VERSION 5.8 ;

BUSBITCHARS "[]" ;

DIVIDERCHAR "/" ;

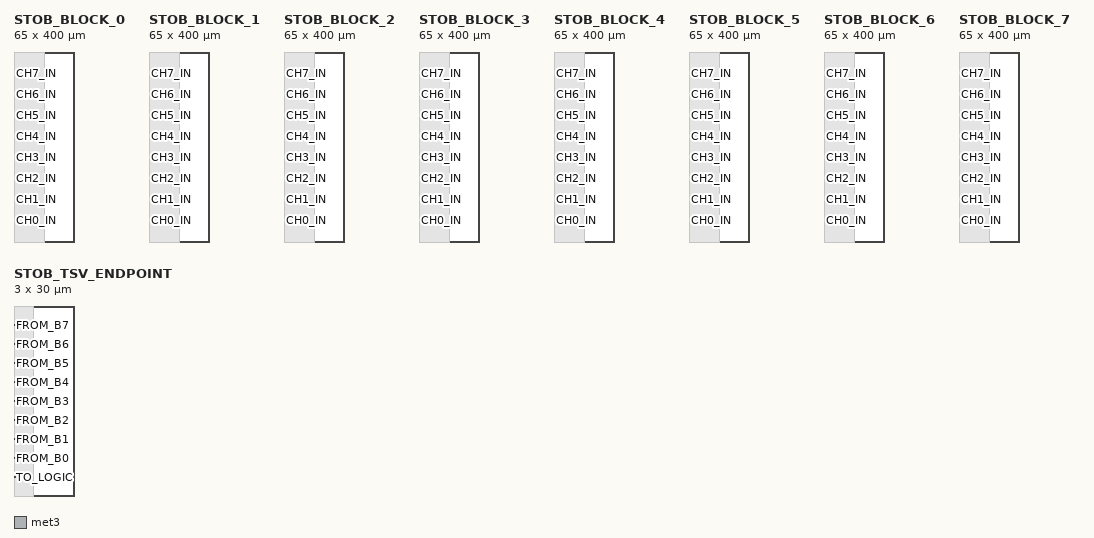
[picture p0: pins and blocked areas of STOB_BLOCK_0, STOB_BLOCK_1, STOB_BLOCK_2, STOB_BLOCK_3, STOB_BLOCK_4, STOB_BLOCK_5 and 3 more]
MACRO STOB_BLOCK_0
  CLASS BLOCK ;
  ORIGIN 0 0 ;
  FOREIGN STOB_BLOCK_0 0 0 ;
  SIZE 65.000000 BY 400.000000 ;
  SYMMETRY X Y ;
  PIN CH0_IN
    DIRECTION INPUT ;
    USE SIGNAL ;
    PORT
      LAYER met3 ;
        RECT 0.000000 44.244444 0.200000 44.644444 ;
    END
  END CH0_IN
  PIN CH0_OUT
    DIRECTION OUTPUT ;
    USE SIGNAL ;
    PORT
      LAYER met3 ;
        RECT 64.800000 44.244444 65.000000 44.644444 ;
    END
  END CH0_OUT
  PIN CH1_IN
    DIRECTION INPUT ;
    USE SIGNAL ;
    PORT
      LAYER met3 ;
        RECT 0.000000 88.688889 0.200000 89.088889 ;
    END
  END CH1_IN
  PIN CH1_OUT
    DIRECTION OUTPUT ;
    USE SIGNAL ;
    PORT
      LAYER met3 ;
        RECT 64.800000 88.688889 65.000000 89.088889 ;
    END
  END CH1_OUT
  PIN CH2_IN
    DIRECTION INPUT ;
    USE SIGNAL ;
    PORT
      LAYER met3 ;
        RECT 0.000000 133.133333 0.200000 133.533333 ;
    END
  END CH2_IN
  PIN CH2_OUT
    DIRECTION OUTPUT ;
    USE SIGNAL ;
    PORT
      LAYER met3 ;
        RECT 64.800000 133.133333 65.000000 133.533333 ;
    END
  END CH2_OUT
  PIN CH3_IN
    DIRECTION INPUT ;
    USE SIGNAL ;
    PORT
      LAYER met3 ;
        RECT 0.000000 177.577778 0.200000 177.977778 ;
    END
  END CH3_IN
  PIN CH3_OUT
    DIRECTION OUTPUT ;
    USE SIGNAL ;
    PORT
      LAYER met3 ;
        RECT 64.800000 177.577778 65.000000 177.977778 ;
    END
  END CH3_OUT
  PIN CH4_IN
    DIRECTION INPUT ;
    USE SIGNAL ;
    PORT
      LAYER met3 ;
        RECT 0.000000 222.022222 0.200000 222.422222 ;
    END
  END CH4_IN
  PIN CH4_OUT
    DIRECTION OUTPUT ;
    USE SIGNAL ;
    PORT
      LAYER met3 ;
        RECT 64.800000 222.022222 65.000000 222.422222 ;
    END
  END CH4_OUT
  PIN CH5_IN
    DIRECTION INPUT ;
    USE SIGNAL ;
    PORT
      LAYER met3 ;
        RECT 0.000000 266.466667 0.200000 266.866667 ;
    END
  END CH5_IN
  PIN CH5_OUT
    DIRECTION OUTPUT ;
    USE SIGNAL ;
    PORT
      LAYER met3 ;
        RECT 64.800000 266.466667 65.000000 266.866667 ;
    END
  END CH5_OUT
  PIN CH6_IN
    DIRECTION INPUT ;
    USE SIGNAL ;
    PORT
      LAYER met3 ;
        RECT 0.000000 310.911111 0.200000 311.311111 ;
    END
  END CH6_IN
  PIN CH6_OUT
    DIRECTION OUTPUT ;
    USE SIGNAL ;
    PORT
      LAYER met3 ;
        RECT 64.800000 310.911111 65.000000 311.311111 ;
    END
  END CH6_OUT
  PIN CH7_IN
    DIRECTION INPUT ;
    USE SIGNAL ;
    PORT
      LAYER met3 ;
        RECT 0.000000 355.355556 0.200000 355.755556 ;
    END
  END CH7_IN
  PIN CH7_OUT
    DIRECTION OUTPUT ;
    USE SIGNAL ;
    PORT
      LAYER met3 ;
        RECT 64.800000 355.355556 65.000000 355.755556 ;
    END
  END CH7_OUT
  OBS
    LAYER met1 ;
      RECT 0 0 65.000000 400.000000 ;
    LAYER met2 ;
      RECT 0 0 65.000000 400.000000 ;
    LAYER met4 ;
      RECT 0 0 65.000000 400.000000 ;
  END
END STOB_BLOCK_0

MACRO STOB_BLOCK_1
  CLASS BLOCK ;
  ORIGIN 0 0 ;
  FOREIGN STOB_BLOCK_1 0 0 ;
  SIZE 65.000000 BY 400.000000 ;
  SYMMETRY X Y ;
  PIN CH0_IN
    DIRECTION INPUT ;
    USE SIGNAL ;
    PORT
      LAYER met3 ;
        RECT 0.000000 44.244444 0.200000 44.644444 ;
    END
  END CH0_IN
  PIN CH0_OUT
    DIRECTION OUTPUT ;
    USE SIGNAL ;
    PORT
      LAYER met3 ;
        RECT 64.800000 44.244444 65.000000 44.644444 ;
    END
  END CH0_OUT
  PIN CH1_IN
    DIRECTION INPUT ;
    USE SIGNAL ;
    PORT
      LAYER met3 ;
        RECT 0.000000 88.688889 0.200000 89.088889 ;
    END
  END CH1_IN
  PIN CH1_OUT
    DIRECTION OUTPUT ;
    USE SIGNAL ;
    PORT
      LAYER met3 ;
        RECT 64.800000 88.688889 65.000000 89.088889 ;
    END
  END CH1_OUT
  PIN CH2_IN
    DIRECTION INPUT ;
    USE SIGNAL ;
    PORT
      LAYER met3 ;
        RECT 0.000000 133.133333 0.200000 133.533333 ;
    END
  END CH2_IN
  PIN CH2_OUT
    DIRECTION OUTPUT ;
    USE SIGNAL ;
    PORT
      LAYER met3 ;
        RECT 64.800000 133.133333 65.000000 133.533333 ;
    END
  END CH2_OUT
  PIN CH3_IN
    DIRECTION INPUT ;
    USE SIGNAL ;
    PORT
      LAYER met3 ;
        RECT 0.000000 177.577778 0.200000 177.977778 ;
    END
  END CH3_IN
  PIN CH3_OUT
    DIRECTION OUTPUT ;
    USE SIGNAL ;
    PORT
      LAYER met3 ;
        RECT 64.800000 177.577778 65.000000 177.977778 ;
    END
  END CH3_OUT
  PIN CH4_IN
    DIRECTION INPUT ;
    USE SIGNAL ;
    PORT
      LAYER met3 ;
        RECT 0.000000 222.022222 0.200000 222.422222 ;
    END
  END CH4_IN
  PIN CH4_OUT
    DIRECTION OUTPUT ;
    USE SIGNAL ;
    PORT
      LAYER met3 ;
        RECT 64.800000 222.022222 65.000000 222.422222 ;
    END
  END CH4_OUT
  PIN CH5_IN
    DIRECTION INPUT ;
    USE SIGNAL ;
    PORT
      LAYER met3 ;
        RECT 0.000000 266.466667 0.200000 266.866667 ;
    END
  END CH5_IN
  PIN CH5_OUT
    DIRECTION OUTPUT ;
    USE SIGNAL ;
    PORT
      LAYER met3 ;
        RECT 64.800000 266.466667 65.000000 266.866667 ;
    END
  END CH5_OUT
  PIN CH6_IN
    DIRECTION INPUT ;
    USE SIGNAL ;
    PORT
      LAYER met3 ;
        RECT 0.000000 310.911111 0.200000 311.311111 ;
    END
  END CH6_IN
  PIN CH6_OUT
    DIRECTION OUTPUT ;
    USE SIGNAL ;
    PORT
      LAYER met3 ;
        RECT 64.800000 310.911111 65.000000 311.311111 ;
    END
  END CH6_OUT
  PIN CH7_IN
    DIRECTION INPUT ;
    USE SIGNAL ;
    PORT
      LAYER met3 ;
        RECT 0.000000 355.355556 0.200000 355.755556 ;
    END
  END CH7_IN
  PIN CH7_OUT
    DIRECTION OUTPUT ;
    USE SIGNAL ;
    PORT
      LAYER met3 ;
        RECT 64.800000 355.355556 65.000000 355.755556 ;
    END
  END CH7_OUT
  OBS
    LAYER met1 ;
      RECT 0 0 65.000000 400.000000 ;
    LAYER met2 ;
      RECT 0 0 65.000000 400.000000 ;
    LAYER met4 ;
      RECT 0 0 65.000000 400.000000 ;
  END
END STOB_BLOCK_1

MACRO STOB_BLOCK_2
  CLASS BLOCK ;
  ORIGIN 0 0 ;
  FOREIGN STOB_BLOCK_2 0 0 ;
  SIZE 65.000000 BY 400.000000 ;
  SYMMETRY X Y ;
  PIN CH0_IN
    DIRECTION INPUT ;
    USE SIGNAL ;
    PORT
      LAYER met3 ;
        RECT 0.000000 44.244444 0.200000 44.644444 ;
    END
  END CH0_IN
  PIN CH0_OUT
    DIRECTION OUTPUT ;
    USE SIGNAL ;
    PORT
      LAYER met3 ;
        RECT 64.800000 44.244444 65.000000 44.644444 ;
    END
  END CH0_OUT
  PIN CH1_IN
    DIRECTION INPUT ;
    USE SIGNAL ;
    PORT
      LAYER met3 ;
        RECT 0.000000 88.688889 0.200000 89.088889 ;
    END
  END CH1_IN
  PIN CH1_OUT
    DIRECTION OUTPUT ;
    USE SIGNAL ;
    PORT
      LAYER met3 ;
        RECT 64.800000 88.688889 65.000000 89.088889 ;
    END
  END CH1_OUT
  PIN CH2_IN
    DIRECTION INPUT ;
    USE SIGNAL ;
    PORT
      LAYER met3 ;
        RECT 0.000000 133.133333 0.200000 133.533333 ;
    END
  END CH2_IN
  PIN CH2_OUT
    DIRECTION OUTPUT ;
    USE SIGNAL ;
    PORT
      LAYER met3 ;
        RECT 64.800000 133.133333 65.000000 133.533333 ;
    END
  END CH2_OUT
  PIN CH3_IN
    DIRECTION INPUT ;
    USE SIGNAL ;
    PORT
      LAYER met3 ;
        RECT 0.000000 177.577778 0.200000 177.977778 ;
    END
  END CH3_IN
  PIN CH3_OUT
    DIRECTION OUTPUT ;
    USE SIGNAL ;
    PORT
      LAYER met3 ;
        RECT 64.800000 177.577778 65.000000 177.977778 ;
    END
  END CH3_OUT
  PIN CH4_IN
    DIRECTION INPUT ;
    USE SIGNAL ;
    PORT
      LAYER met3 ;
        RECT 0.000000 222.022222 0.200000 222.422222 ;
    END
  END CH4_IN
  PIN CH4_OUT
    DIRECTION OUTPUT ;
    USE SIGNAL ;
    PORT
      LAYER met3 ;
        RECT 64.800000 222.022222 65.000000 222.422222 ;
    END
  END CH4_OUT
  PIN CH5_IN
    DIRECTION INPUT ;
    USE SIGNAL ;
    PORT
      LAYER met3 ;
        RECT 0.000000 266.466667 0.200000 266.866667 ;
    END
  END CH5_IN
  PIN CH5_OUT
    DIRECTION OUTPUT ;
    USE SIGNAL ;
    PORT
      LAYER met3 ;
        RECT 64.800000 266.466667 65.000000 266.866667 ;
    END
  END CH5_OUT
  PIN CH6_IN
    DIRECTION INPUT ;
    USE SIGNAL ;
    PORT
      LAYER met3 ;
        RECT 0.000000 310.911111 0.200000 311.311111 ;
    END
  END CH6_IN
  PIN CH6_OUT
    DIRECTION OUTPUT ;
    USE SIGNAL ;
    PORT
      LAYER met3 ;
        RECT 64.800000 310.911111 65.000000 311.311111 ;
    END
  END CH6_OUT
  PIN CH7_IN
    DIRECTION INPUT ;
    USE SIGNAL ;
    PORT
      LAYER met3 ;
        RECT 0.000000 355.355556 0.200000 355.755556 ;
    END
  END CH7_IN
  PIN CH7_OUT
    DIRECTION OUTPUT ;
    USE SIGNAL ;
    PORT
      LAYER met3 ;
        RECT 64.800000 355.355556 65.000000 355.755556 ;
    END
  END CH7_OUT
  OBS
    LAYER met1 ;
      RECT 0 0 65.000000 400.000000 ;
    LAYER met2 ;
      RECT 0 0 65.000000 400.000000 ;
    LAYER met4 ;
      RECT 0 0 65.000000 400.000000 ;
  END
END STOB_BLOCK_2

MACRO STOB_BLOCK_3
  CLASS BLOCK ;
  ORIGIN 0 0 ;
  FOREIGN STOB_BLOCK_3 0 0 ;
  SIZE 65.000000 BY 400.000000 ;
  SYMMETRY X Y ;
  PIN CH0_IN
    DIRECTION INPUT ;
    USE SIGNAL ;
    PORT
      LAYER met3 ;
        RECT 0.000000 44.244444 0.200000 44.644444 ;
    END
  END CH0_IN
  PIN CH0_OUT
    DIRECTION OUTPUT ;
    USE SIGNAL ;
    PORT
      LAYER met3 ;
        RECT 64.800000 44.244444 65.000000 44.644444 ;
    END
  END CH0_OUT
  PIN CH1_IN
    DIRECTION INPUT ;
    USE SIGNAL ;
    PORT
      LAYER met3 ;
        RECT 0.000000 88.688889 0.200000 89.088889 ;
    END
  END CH1_IN
  PIN CH1_OUT
    DIRECTION OUTPUT ;
    USE SIGNAL ;
    PORT
      LAYER met3 ;
        RECT 64.800000 88.688889 65.000000 89.088889 ;
    END
  END CH1_OUT
  PIN CH2_IN
    DIRECTION INPUT ;
    USE SIGNAL ;
    PORT
      LAYER met3 ;
        RECT 0.000000 133.133333 0.200000 133.533333 ;
    END
  END CH2_IN
  PIN CH2_OUT
    DIRECTION OUTPUT ;
    USE SIGNAL ;
    PORT
      LAYER met3 ;
        RECT 64.800000 133.133333 65.000000 133.533333 ;
    END
  END CH2_OUT
  PIN CH3_IN
    DIRECTION INPUT ;
    USE SIGNAL ;
    PORT
      LAYER met3 ;
        RECT 0.000000 177.577778 0.200000 177.977778 ;
    END
  END CH3_IN
  PIN CH3_OUT
    DIRECTION OUTPUT ;
    USE SIGNAL ;
    PORT
      LAYER met3 ;
        RECT 64.800000 177.577778 65.000000 177.977778 ;
    END
  END CH3_OUT
  PIN CH4_IN
    DIRECTION INPUT ;
    USE SIGNAL ;
    PORT
      LAYER met3 ;
        RECT 0.000000 222.022222 0.200000 222.422222 ;
    END
  END CH4_IN
  PIN CH4_OUT
    DIRECTION OUTPUT ;
    USE SIGNAL ;
    PORT
      LAYER met3 ;
        RECT 64.800000 222.022222 65.000000 222.422222 ;
    END
  END CH4_OUT
  PIN CH5_IN
    DIRECTION INPUT ;
    USE SIGNAL ;
    PORT
      LAYER met3 ;
        RECT 0.000000 266.466667 0.200000 266.866667 ;
    END
  END CH5_IN
  PIN CH5_OUT
    DIRECTION OUTPUT ;
    USE SIGNAL ;
    PORT
      LAYER met3 ;
        RECT 64.800000 266.466667 65.000000 266.866667 ;
    END
  END CH5_OUT
  PIN CH6_IN
    DIRECTION INPUT ;
    USE SIGNAL ;
    PORT
      LAYER met3 ;
        RECT 0.000000 310.911111 0.200000 311.311111 ;
    END
  END CH6_IN
  PIN CH6_OUT
    DIRECTION OUTPUT ;
    USE SIGNAL ;
    PORT
      LAYER met3 ;
        RECT 64.800000 310.911111 65.000000 311.311111 ;
    END
  END CH6_OUT
  PIN CH7_IN
    DIRECTION INPUT ;
    USE SIGNAL ;
    PORT
      LAYER met3 ;
        RECT 0.000000 355.355556 0.200000 355.755556 ;
    END
  END CH7_IN
  PIN CH7_OUT
    DIRECTION OUTPUT ;
    USE SIGNAL ;
    PORT
      LAYER met3 ;
        RECT 64.800000 355.355556 65.000000 355.755556 ;
    END
  END CH7_OUT
  OBS
    LAYER met1 ;
      RECT 0 0 65.000000 400.000000 ;
    LAYER met2 ;
      RECT 0 0 65.000000 400.000000 ;
    LAYER met4 ;
      RECT 0 0 65.000000 400.000000 ;
  END
END STOB_BLOCK_3

MACRO STOB_BLOCK_4
  CLASS BLOCK ;
  ORIGIN 0 0 ;
  FOREIGN STOB_BLOCK_4 0 0 ;
  SIZE 65.000000 BY 400.000000 ;
  SYMMETRY X Y ;
  PIN CH0_IN
    DIRECTION INPUT ;
    USE SIGNAL ;
    PORT
      LAYER met3 ;
        RECT 0.000000 44.244444 0.200000 44.644444 ;
    END
  END CH0_IN
  PIN CH0_OUT
    DIRECTION OUTPUT ;
    USE SIGNAL ;
    PORT
      LAYER met3 ;
        RECT 64.800000 44.244444 65.000000 44.644444 ;
    END
  END CH0_OUT
  PIN CH1_IN
    DIRECTION INPUT ;
    USE SIGNAL ;
    PORT
      LAYER met3 ;
        RECT 0.000000 88.688889 0.200000 89.088889 ;
    END
  END CH1_IN
  PIN CH1_OUT
    DIRECTION OUTPUT ;
    USE SIGNAL ;
    PORT
      LAYER met3 ;
        RECT 64.800000 88.688889 65.000000 89.088889 ;
    END
  END CH1_OUT
  PIN CH2_IN
    DIRECTION INPUT ;
    USE SIGNAL ;
    PORT
      LAYER met3 ;
        RECT 0.000000 133.133333 0.200000 133.533333 ;
    END
  END CH2_IN
  PIN CH2_OUT
    DIRECTION OUTPUT ;
    USE SIGNAL ;
    PORT
      LAYER met3 ;
        RECT 64.800000 133.133333 65.000000 133.533333 ;
    END
  END CH2_OUT
  PIN CH3_IN
    DIRECTION INPUT ;
    USE SIGNAL ;
    PORT
      LAYER met3 ;
        RECT 0.000000 177.577778 0.200000 177.977778 ;
    END
  END CH3_IN
  PIN CH3_OUT
    DIRECTION OUTPUT ;
    USE SIGNAL ;
    PORT
      LAYER met3 ;
        RECT 64.800000 177.577778 65.000000 177.977778 ;
    END
  END CH3_OUT
  PIN CH4_IN
    DIRECTION INPUT ;
    USE SIGNAL ;
    PORT
      LAYER met3 ;
        RECT 0.000000 222.022222 0.200000 222.422222 ;
    END
  END CH4_IN
  PIN CH4_OUT
    DIRECTION OUTPUT ;
    USE SIGNAL ;
    PORT
      LAYER met3 ;
        RECT 64.800000 222.022222 65.000000 222.422222 ;
    END
  END CH4_OUT
  PIN CH5_IN
    DIRECTION INPUT ;
    USE SIGNAL ;
    PORT
      LAYER met3 ;
        RECT 0.000000 266.466667 0.200000 266.866667 ;
    END
  END CH5_IN
  PIN CH5_OUT
    DIRECTION OUTPUT ;
    USE SIGNAL ;
    PORT
      LAYER met3 ;
        RECT 64.800000 266.466667 65.000000 266.866667 ;
    END
  END CH5_OUT
  PIN CH6_IN
    DIRECTION INPUT ;
    USE SIGNAL ;
    PORT
      LAYER met3 ;
        RECT 0.000000 310.911111 0.200000 311.311111 ;
    END
  END CH6_IN
  PIN CH6_OUT
    DIRECTION OUTPUT ;
    USE SIGNAL ;
    PORT
      LAYER met3 ;
        RECT 64.800000 310.911111 65.000000 311.311111 ;
    END
  END CH6_OUT
  PIN CH7_IN
    DIRECTION INPUT ;
    USE SIGNAL ;
    PORT
      LAYER met3 ;
        RECT 0.000000 355.355556 0.200000 355.755556 ;
    END
  END CH7_IN
  PIN CH7_OUT
    DIRECTION OUTPUT ;
    USE SIGNAL ;
    PORT
      LAYER met3 ;
        RECT 64.800000 355.355556 65.000000 355.755556 ;
    END
  END CH7_OUT
  OBS
    LAYER met1 ;
      RECT 0 0 65.000000 400.000000 ;
    LAYER met2 ;
      RECT 0 0 65.000000 400.000000 ;
    LAYER met4 ;
      RECT 0 0 65.000000 400.000000 ;
  END
END STOB_BLOCK_4

MACRO STOB_BLOCK_5
  CLASS BLOCK ;
  ORIGIN 0 0 ;
  FOREIGN STOB_BLOCK_5 0 0 ;
  SIZE 65.000000 BY 400.000000 ;
  SYMMETRY X Y ;
  PIN CH0_IN
    DIRECTION INPUT ;
    USE SIGNAL ;
    PORT
      LAYER met3 ;
        RECT 0.000000 44.244444 0.200000 44.644444 ;
    END
  END CH0_IN
  PIN CH0_OUT
    DIRECTION OUTPUT ;
    USE SIGNAL ;
    PORT
      LAYER met3 ;
        RECT 64.800000 44.244444 65.000000 44.644444 ;
    END
  END CH0_OUT
  PIN CH1_IN
    DIRECTION INPUT ;
    USE SIGNAL ;
    PORT
      LAYER met3 ;
        RECT 0.000000 88.688889 0.200000 89.088889 ;
    END
  END CH1_IN
  PIN CH1_OUT
    DIRECTION OUTPUT ;
    USE SIGNAL ;
    PORT
      LAYER met3 ;
        RECT 64.800000 88.688889 65.000000 89.088889 ;
    END
  END CH1_OUT
  PIN CH2_IN
    DIRECTION INPUT ;
    USE SIGNAL ;
    PORT
      LAYER met3 ;
        RECT 0.000000 133.133333 0.200000 133.533333 ;
    END
  END CH2_IN
  PIN CH2_OUT
    DIRECTION OUTPUT ;
    USE SIGNAL ;
    PORT
      LAYER met3 ;
        RECT 64.800000 133.133333 65.000000 133.533333 ;
    END
  END CH2_OUT
  PIN CH3_IN
    DIRECTION INPUT ;
    USE SIGNAL ;
    PORT
      LAYER met3 ;
        RECT 0.000000 177.577778 0.200000 177.977778 ;
    END
  END CH3_IN
  PIN CH3_OUT
    DIRECTION OUTPUT ;
    USE SIGNAL ;
    PORT
      LAYER met3 ;
        RECT 64.800000 177.577778 65.000000 177.977778 ;
    END
  END CH3_OUT
  PIN CH4_IN
    DIRECTION INPUT ;
    USE SIGNAL ;
    PORT
      LAYER met3 ;
        RECT 0.000000 222.022222 0.200000 222.422222 ;
    END
  END CH4_IN
  PIN CH4_OUT
    DIRECTION OUTPUT ;
    USE SIGNAL ;
    PORT
      LAYER met3 ;
        RECT 64.800000 222.022222 65.000000 222.422222 ;
    END
  END CH4_OUT
  PIN CH5_IN
    DIRECTION INPUT ;
    USE SIGNAL ;
    PORT
      LAYER met3 ;
        RECT 0.000000 266.466667 0.200000 266.866667 ;
    END
  END CH5_IN
  PIN CH5_OUT
    DIRECTION OUTPUT ;
    USE SIGNAL ;
    PORT
      LAYER met3 ;
        RECT 64.800000 266.466667 65.000000 266.866667 ;
    END
  END CH5_OUT
  PIN CH6_IN
    DIRECTION INPUT ;
    USE SIGNAL ;
    PORT
      LAYER met3 ;
        RECT 0.000000 310.911111 0.200000 311.311111 ;
    END
  END CH6_IN
  PIN CH6_OUT
    DIRECTION OUTPUT ;
    USE SIGNAL ;
    PORT
      LAYER met3 ;
        RECT 64.800000 310.911111 65.000000 311.311111 ;
    END
  END CH6_OUT
  PIN CH7_IN
    DIRECTION INPUT ;
    USE SIGNAL ;
    PORT
      LAYER met3 ;
        RECT 0.000000 355.355556 0.200000 355.755556 ;
    END
  END CH7_IN
  PIN CH7_OUT
    DIRECTION OUTPUT ;
    USE SIGNAL ;
    PORT
      LAYER met3 ;
        RECT 64.800000 355.355556 65.000000 355.755556 ;
    END
  END CH7_OUT
  OBS
    LAYER met1 ;
      RECT 0 0 65.000000 400.000000 ;
    LAYER met2 ;
      RECT 0 0 65.000000 400.000000 ;
    LAYER met4 ;
      RECT 0 0 65.000000 400.000000 ;
  END
END STOB_BLOCK_5

MACRO STOB_BLOCK_6
  CLASS BLOCK ;
  ORIGIN 0 0 ;
  FOREIGN STOB_BLOCK_6 0 0 ;
  SIZE 65.000000 BY 400.000000 ;
  SYMMETRY X Y ;
  PIN CH0_IN
    DIRECTION INPUT ;
    USE SIGNAL ;
    PORT
      LAYER met3 ;
        RECT 0.000000 44.244444 0.200000 44.644444 ;
    END
  END CH0_IN
  PIN CH0_OUT
    DIRECTION OUTPUT ;
    USE SIGNAL ;
    PORT
      LAYER met3 ;
        RECT 64.800000 44.244444 65.000000 44.644444 ;
    END
  END CH0_OUT
  PIN CH1_IN
    DIRECTION INPUT ;
    USE SIGNAL ;
    PORT
      LAYER met3 ;
        RECT 0.000000 88.688889 0.200000 89.088889 ;
    END
  END CH1_IN
  PIN CH1_OUT
    DIRECTION OUTPUT ;
    USE SIGNAL ;
    PORT
      LAYER met3 ;
        RECT 64.800000 88.688889 65.000000 89.088889 ;
    END
  END CH1_OUT
  PIN CH2_IN
    DIRECTION INPUT ;
    USE SIGNAL ;
    PORT
      LAYER met3 ;
        RECT 0.000000 133.133333 0.200000 133.533333 ;
    END
  END CH2_IN
  PIN CH2_OUT
    DIRECTION OUTPUT ;
    USE SIGNAL ;
    PORT
      LAYER met3 ;
        RECT 64.800000 133.133333 65.000000 133.533333 ;
    END
  END CH2_OUT
  PIN CH3_IN
    DIRECTION INPUT ;
    USE SIGNAL ;
    PORT
      LAYER met3 ;
        RECT 0.000000 177.577778 0.200000 177.977778 ;
    END
  END CH3_IN
  PIN CH3_OUT
    DIRECTION OUTPUT ;
    USE SIGNAL ;
    PORT
      LAYER met3 ;
        RECT 64.800000 177.577778 65.000000 177.977778 ;
    END
  END CH3_OUT
  PIN CH4_IN
    DIRECTION INPUT ;
    USE SIGNAL ;
    PORT
      LAYER met3 ;
        RECT 0.000000 222.022222 0.200000 222.422222 ;
    END
  END CH4_IN
  PIN CH4_OUT
    DIRECTION OUTPUT ;
    USE SIGNAL ;
    PORT
      LAYER met3 ;
        RECT 64.800000 222.022222 65.000000 222.422222 ;
    END
  END CH4_OUT
  PIN CH5_IN
    DIRECTION INPUT ;
    USE SIGNAL ;
    PORT
      LAYER met3 ;
        RECT 0.000000 266.466667 0.200000 266.866667 ;
    END
  END CH5_IN
  PIN CH5_OUT
    DIRECTION OUTPUT ;
    USE SIGNAL ;
    PORT
      LAYER met3 ;
        RECT 64.800000 266.466667 65.000000 266.866667 ;
    END
  END CH5_OUT
  PIN CH6_IN
    DIRECTION INPUT ;
    USE SIGNAL ;
    PORT
      LAYER met3 ;
        RECT 0.000000 310.911111 0.200000 311.311111 ;
    END
  END CH6_IN
  PIN CH6_OUT
    DIRECTION OUTPUT ;
    USE SIGNAL ;
    PORT
      LAYER met3 ;
        RECT 64.800000 310.911111 65.000000 311.311111 ;
    END
  END CH6_OUT
  PIN CH7_IN
    DIRECTION INPUT ;
    USE SIGNAL ;
    PORT
      LAYER met3 ;
        RECT 0.000000 355.355556 0.200000 355.755556 ;
    END
  END CH7_IN
  PIN CH7_OUT
    DIRECTION OUTPUT ;
    USE SIGNAL ;
    PORT
      LAYER met3 ;
        RECT 64.800000 355.355556 65.000000 355.755556 ;
    END
  END CH7_OUT
  OBS
    LAYER met1 ;
      RECT 0 0 65.000000 400.000000 ;
    LAYER met2 ;
      RECT 0 0 65.000000 400.000000 ;
    LAYER met4 ;
      RECT 0 0 65.000000 400.000000 ;
  END
END STOB_BLOCK_6

MACRO STOB_BLOCK_7
  CLASS BLOCK ;
  ORIGIN 0 0 ;
  FOREIGN STOB_BLOCK_7 0 0 ;
  SIZE 65.000000 BY 400.000000 ;
  SYMMETRY X Y ;
  PIN CH0_IN
    DIRECTION INPUT ;
    USE SIGNAL ;
    PORT
      LAYER met3 ;
        RECT 0.000000 44.244444 0.200000 44.644444 ;
    END
  END CH0_IN
  PIN CH0_OUT
    DIRECTION OUTPUT ;
    USE SIGNAL ;
    PORT
      LAYER met3 ;
        RECT 64.800000 44.244444 65.000000 44.644444 ;
    END
  END CH0_OUT
  PIN CH1_IN
    DIRECTION INPUT ;
    USE SIGNAL ;
    PORT
      LAYER met3 ;
        RECT 0.000000 88.688889 0.200000 89.088889 ;
    END
  END CH1_IN
  PIN CH1_OUT
    DIRECTION OUTPUT ;
    USE SIGNAL ;
    PORT
      LAYER met3 ;
        RECT 64.800000 88.688889 65.000000 89.088889 ;
    END
  END CH1_OUT
  PIN CH2_IN
    DIRECTION INPUT ;
    USE SIGNAL ;
    PORT
      LAYER met3 ;
        RECT 0.000000 133.133333 0.200000 133.533333 ;
    END
  END CH2_IN
  PIN CH2_OUT
    DIRECTION OUTPUT ;
    USE SIGNAL ;
    PORT
      LAYER met3 ;
        RECT 64.800000 133.133333 65.000000 133.533333 ;
    END
  END CH2_OUT
  PIN CH3_IN
    DIRECTION INPUT ;
    USE SIGNAL ;
    PORT
      LAYER met3 ;
        RECT 0.000000 177.577778 0.200000 177.977778 ;
    END
  END CH3_IN
  PIN CH3_OUT
    DIRECTION OUTPUT ;
    USE SIGNAL ;
    PORT
      LAYER met3 ;
        RECT 64.800000 177.577778 65.000000 177.977778 ;
    END
  END CH3_OUT
  PIN CH4_IN
    DIRECTION INPUT ;
    USE SIGNAL ;
    PORT
      LAYER met3 ;
        RECT 0.000000 222.022222 0.200000 222.422222 ;
    END
  END CH4_IN
  PIN CH4_OUT
    DIRECTION OUTPUT ;
    USE SIGNAL ;
    PORT
      LAYER met3 ;
        RECT 64.800000 222.022222 65.000000 222.422222 ;
    END
  END CH4_OUT
  PIN CH5_IN
    DIRECTION INPUT ;
    USE SIGNAL ;
    PORT
      LAYER met3 ;
        RECT 0.000000 266.466667 0.200000 266.866667 ;
    END
  END CH5_IN
  PIN CH5_OUT
    DIRECTION OUTPUT ;
    USE SIGNAL ;
    PORT
      LAYER met3 ;
        RECT 64.800000 266.466667 65.000000 266.866667 ;
    END
  END CH5_OUT
  PIN CH6_IN
    DIRECTION INPUT ;
    USE SIGNAL ;
    PORT
      LAYER met3 ;
        RECT 0.000000 310.911111 0.200000 311.311111 ;
    END
  END CH6_IN
  PIN CH6_OUT
    DIRECTION OUTPUT ;
    USE SIGNAL ;
    PORT
      LAYER met3 ;
        RECT 64.800000 310.911111 65.000000 311.311111 ;
    END
  END CH6_OUT
  PIN CH7_IN
    DIRECTION INPUT ;
    USE SIGNAL ;
    PORT
      LAYER met3 ;
        RECT 0.000000 355.355556 0.200000 355.755556 ;
    END
  END CH7_IN
  PIN CH7_OUT
    DIRECTION OUTPUT ;
    USE SIGNAL ;
    PORT
      LAYER met3 ;
        RECT 64.800000 355.355556 65.000000 355.755556 ;
    END
  END CH7_OUT
  OBS
    LAYER met1 ;
      RECT 0 0 65.000000 400.000000 ;
    LAYER met2 ;
      RECT 0 0 65.000000 400.000000 ;
    LAYER met4 ;
      RECT 0 0 65.000000 400.000000 ;
  END
END STOB_BLOCK_7

MACRO STOB_TSV_ENDPOINT
  CLASS BLOCK ;
  ORIGIN 0 0 ;
  FOREIGN STOB_TSV_ENDPOINT 0 0 ;
  SIZE 3.000000 BY 30.000000 ;
  SYMMETRY X Y ;
  PIN TO_LOGIC
    DIRECTION OUTPUT ;
    USE SIGNAL ;
    PORT
      LAYER met3 ;
        RECT 0 2.900000 0.3 3.100000 ;
    END
  END TO_LOGIC
  PIN FROM_B0
    DIRECTION INPUT ;
    USE SIGNAL ;
    PORT
      LAYER met3 ;
        RECT 0 5.900000 0.3 6.100000 ;
    END
  END FROM_B0
  PIN FROM_B1
    DIRECTION INPUT ;
    USE SIGNAL ;
    PORT
      LAYER met3 ;
        RECT 0 8.900000 0.3 9.100000 ;
    END
  END FROM_B1
  PIN FROM_B2
    DIRECTION INPUT ;
    USE SIGNAL ;
    PORT
      LAYER met3 ;
        RECT 0 11.900000 0.3 12.100000 ;
    END
  END FROM_B2
  PIN FROM_B3
    DIRECTION INPUT ;
    USE SIGNAL ;
    PORT
      LAYER met3 ;
        RECT 0 14.900000 0.3 15.100000 ;
    END
  END FROM_B3
  PIN FROM_B4
    DIRECTION INPUT ;
    USE SIGNAL ;
    PORT
      LAYER met3 ;
        RECT 0 17.900000 0.3 18.100000 ;
    END
  END FROM_B4
  PIN FROM_B5
    DIRECTION INPUT ;
    USE SIGNAL ;
    PORT
      LAYER met3 ;
        RECT 0 20.900000 0.3 21.100000 ;
    END
  END FROM_B5
  PIN FROM_B6
    DIRECTION INPUT ;
    USE SIGNAL ;
    PORT
      LAYER met3 ;
        RECT 0 23.900000 0.3 24.100000 ;
    END
  END FROM_B6
  PIN FROM_B7
    DIRECTION INPUT ;
    USE SIGNAL ;
    PORT
      LAYER met3 ;
        RECT 0 26.900000 0.3 27.100000 ;
    END
  END FROM_B7
  OBS
    LAYER met1 ;
      RECT 0 0 3.000000 30.000000 ;
    LAYER met2 ;
      RECT 0 0 3.000000 30.000000 ;
    LAYER met4 ;
      RECT 0 0 3.000000 30.000000 ;
  END
END STOB_TSV_ENDPOINT

END LIBRARY
